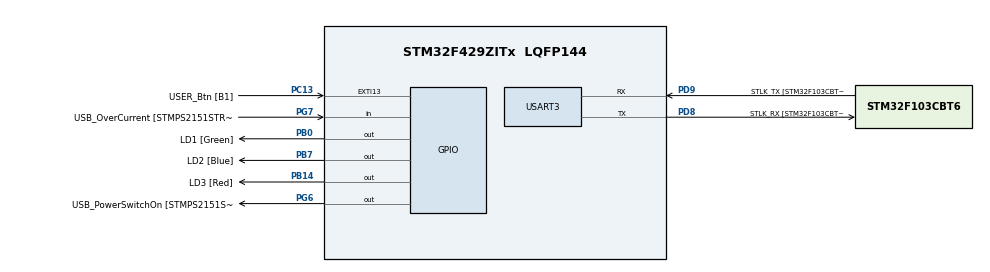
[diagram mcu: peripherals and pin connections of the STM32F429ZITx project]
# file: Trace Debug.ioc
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Mcu.Family=STM32F4
Mcu.Name=STM32F429ZITx
Mcu.Package=LQFP144
NVIC.PriorityGroup=NVIC_PRIORITYGROUP_4
PA13.GPIO_Label=TMS
PA13.Mode=Trace_Asynchronous_SW
PA13.Signal=SYS_JTMS-SWDIO
PA14.GPIO_Label=TCK
PA14.Mode=Trace_Asynchronous_SW
PA14.Signal=SYS_JTCK-SWCLK
PB0.GPIO_Label=LD1 [Green]
PB0.Signal=GPIO_Output
PB13.GPIO_Label=RMII_TXD1 [LAN8742A-CZ-TR_TXD1]
PB13.Signal=ETH_TXD1
PB14.GPIO_Label=LD3 [Red]
PB14.Signal=GPIO_Output
PB3.Mode=Trace_Asynchronous_SW
PB3.Signal=SYS_JTDO-SWO
PB7.GPIO_Label=LD2 [Blue]
PB7.Signal=GPIO_Output
PC13.GPIO_Label=USER_Btn [B1]
PC13.Signal=GPXTI13
PC14/OSC32_IN.Mode=LSE-External-Oscillator
PC14/OSC32_IN.Signal=RCC_OSC32_IN
PC15/OSC32_OUT.Mode=LSE-External-Oscillator
PC15/OSC32_OUT.Signal=RCC_OSC32_OUT
PD8.GPIO_Label=STLK_RX [STM32F103CBT6_PA3]
PD8.Mode=Asynchronous
PD8.Signal=USART3_TX
PD9.GPIO_Label=STLK_TX [STM32F103CBT6_PA2]
PD9.Mode=Asynchronous
PD9.Signal=USART3_RX
PG6.GPIO_Label=USB_PowerSwitchOn [STMPS2151STR_EN]
PG6.Signal=GPIO_Output
PG7.GPIO_Label=USB_OverCurrent [STMPS2151STR_FAULT]
PG7.Signal=GPIO_Input
PH0/OSC_IN.GPIO_Label=MCO [STM32F103CBT6_PA8]
PH0/OSC_IN.Mode=HSE-External-Clock-Source
PH0/OSC_IN.Signal=RCC_OSC_IN
PH1/OSC_OUT.Mode=HSE-External-Clock-Source
PH1/OSC_OUT.Signal=RCC_OSC_OUT
ProjectManager.HeapSize=0x800
ProjectManager.StackSize=0x800
ProjectManager.TargetToolchain=MDK-ARM V5.32
RCC.48MHZClocksFreq_Value=19428571.42857143
RCC.AHBFreq_Value=68000000
RCC.APB1CLKDivider=RCC_HCLK_DIV2
RCC.APB1Freq_Value=34000000
RCC.APB1TimFreq_Value=68000000
RCC.APB2CLKDivider=RCC_HCLK_DIV2
RCC.APB2Freq_Value=34000000
RCC.APB2TimFreq_Value=68000000
RCC.CortexFreq_Value=68000000
RCC.HCLKFreq_Value=68000000
RCC.HSE_VALUE=8000000
RCC.HSI_VALUE=16000000
RCC.PLLM=4
RCC.PLLMUL=RCC_PLL_MUL9
RCC.PLLN=68
RCC.PLLQ=7
RCC.PLLSourceVirtual=RCC_PLLSOURCE_HSE
RCC.PRESCALERUSB=RCC_USBCLKSOURCE_PLL_DIV1_5
RCC.SYSCLKFreq_VALUE=68000000
RCC.SYSCLKSource=RCC_SYSCLKSOURCE_PLLCLK
RCC.SYSCLKSourceVirtual=RCC_SYSCLKSOURCE_PLLCLK
RCC.USBFreq_Value=48000000
RCC.VCOOutputFreq_Value=136000000
USART3.VirtualMode=VM_ASYNC
board=NUCLEO-F429ZI

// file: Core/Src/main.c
/* USER CODE BEGIN Header */
/**
  ******************************************************************************
  * @file           : main.c
  * @brief          : Main program body
  ******************************************************************************
  * @attention
  *
  * <h2><center>&copy; Copyright (c) 2022 STMicroelectronics.
  * All rights reserved.</center></h2>
  *
  * This software component is licensed by ST under BSD 3-Clause license,
  * the "License"; You may not use this file except in compliance with the
  * License. You may obtain a copy of the License at:
  *                        opensource.org/licenses/BSD-3-Clause
  *
  ******************************************************************************
  */
/* USER CODE END Header */
#include "main.h"
#include "cramel.h"
#include "dwt_counter.h"
#include "math_helper.h"
#include "core_cm4_simd.h"

UART_HandleTypeDef huart3;

int16_t s16_curfitLine[RX_LEN];
float f32_curfitLine[RX_LEN];

/* USER CODE BEGIN PV */
struct __FILE
{
  int handle;
  /* Whatever you require here. If the only file you are using is */
  /* standard output using printf() for debugging, no file handling */
  /* is required. */
};
/* FILE is typedefТd in stdio.h. */
FILE __stdout;
int ferror(FILE *f)
{
  /* Your implementation of ferror(). */
  return 0;
}

int fputc(int ch, FILE *f)
{
  /* Place your implementation of fputc here */
  /* e.g. write a character to the USART1 and Loop until the end of transmission */
  HAL_UART_Transmit(&huart3, (uint8_t *)&ch, 1, 0xFFFF);

  return ch;
}
/* USER CODE END PV */

void SystemClock_Config(void);
static void MX_GPIO_Init(void);
static void MX_USART3_UART_Init(void);

int main(void)
{
  /* USER CODE BEGIN 1 */
	curfitCoef_t curfitCoef;
  uint64_t u64_bitmap;

  int16_t *s16_src;
  uint8_t *u8_curfitComp;
  float *f32_curfitLineRef;
  float f32_snr;
  float f32_accuracy;
  volatile float f32_duration = 0;
  volatile float f32_accuracyFrame = 0;
  /* USER CODE END 1 */

  /* MCU Configuration--------------------------------------------------------*/

  /* Reset of all peripherals, Initializes the Flash interface and the Systick. */
  HAL_Init();

  /* Configure the system clock */
  SystemClock_Config();

  /* Initialize all configured peripherals */
  MX_GPIO_Init();
  MX_USART3_UART_Init();
  /* USER CODE BEGIN 2 */
	SystemCoreClockUpdate();
  printf("\r\nINIT ARMCC OK @ %d MHz\r\n",(uint32_t)SystemCoreClock/1000000);

	uint32_t val1, val2;
	val1 = 1500;
	val2 = 3500;
	printf("\r\nSADD16 %d \r\n",__SADD16(val1, val2));

	for (uint8_t u8_i = 0; u8_i < TX_LEN; u8_i++)
  {
	  /* Set data */
	  s16_src = (int16_t*) &s16_reconstructed[u8_i];
	  u8_curfitComp = (uint8_t*) &u8_curvefitCompare[u8_i];
	  f32_curfitLineRef = (float*) &f32_curvefitLineRef[u8_i];
	  u64_bitmap = u64Func_GetBitmap(u8_curfitComp, RX_LEN);

	  /* Start timer */
	  DWT_Start();

	  /* Estimate */
	  vFunc_CurfitEstimation(s16_src, &curfitCoef, RX_LEN, u64_bitmap);
	  vFunc_GetCurveFitLine(s16_curfitLine, &curfitCoef, RX_LEN);

	  /* Stop timer */
	  f32_duration += DWT_GetTime_us();
	  DWT_Stop();

	  /* Calculate accuracy */
	  vFunc_ConvertS16toFloat(s16_curfitLine, f32_curfitLine, RX_LEN);
	  f32_snr = arm_snr_f32(f32_curfitLineRef, f32_curfitLine, RX_LEN);
	  f32_accuracy = 100.0f - (100.0f / f32_snr);
	  f32_accuracyFrame += f32_accuracy;

	  /* Print to stdout */
	  printf("Accuracy TX[%d]: %.2f %%\r\n", u8_i, f32_accuracy);
  }

	f32_accuracyFrame /= TX_LEN;
  f32_duration /= 1000;

  printf("\r\n");
  printf("Frame Accuracy: %.2f %%\r\n", f32_accuracyFrame);
  printf("Frame Duration: %.2f ms\r\n", f32_duration);
  /* USER CODE END 2 */

  /* Infinite loop */
  while (1)
  {

  }
}

void SystemClock_Config(void)
{
  RCC_OscInitTypeDef RCC_OscInitStruct = {0};
  RCC_ClkInitTypeDef RCC_ClkInitStruct = {0};

  /** Configure the main internal regulator output voltage
  */
  __HAL_RCC_PWR_CLK_ENABLE();
  __HAL_PWR_VOLTAGESCALING_CONFIG(PWR_REGULATOR_VOLTAGE_SCALE1);
  /** Initializes the RCC Oscillators according to the specified parameters
  * in the RCC_OscInitTypeDef structure.
  */
  RCC_OscInitStruct.OscillatorType = RCC_OSCILLATORTYPE_HSE;
  RCC_OscInitStruct.HSEState = RCC_HSE_BYPASS;
  RCC_OscInitStruct.PLL.PLLState = RCC_PLL_ON;
  RCC_OscInitStruct.PLL.PLLSource = RCC_PLLSOURCE_HSE;
  RCC_OscInitStruct.PLL.PLLM = 4;
  RCC_OscInitStruct.PLL.PLLN = 68;
  RCC_OscInitStruct.PLL.PLLP = RCC_PLLP_DIV2;
  RCC_OscInitStruct.PLL.PLLQ = 7;
  if (HAL_RCC_OscConfig(&RCC_OscInitStruct) != HAL_OK)
  {
    Error_Handler();
  }
  /** Initializes the CPU, AHB and APB buses clocks
  */
  RCC_ClkInitStruct.ClockType = RCC_CLOCKTYPE_HCLK|RCC_CLOCKTYPE_SYSCLK
                              |RCC_CLOCKTYPE_PCLK1|RCC_CLOCKTYPE_PCLK2;
  RCC_ClkInitStruct.SYSCLKSource = RCC_SYSCLKSOURCE_PLLCLK;
  RCC_ClkInitStruct.AHBCLKDivider = RCC_SYSCLK_DIV1;
  RCC_ClkInitStruct.APB1CLKDivider = RCC_HCLK_DIV4;
  RCC_ClkInitStruct.APB2CLKDivider = RCC_HCLK_DIV2;

  if (HAL_RCC_ClockConfig(&RCC_ClkInitStruct, FLASH_LATENCY_2) != HAL_OK)
  {
    Error_Handler();
  }
}

static void MX_USART3_UART_Init(void)
{

  huart3.Instance = USART3;
  huart3.Init.BaudRate = 115200;
  huart3.Init.WordLength = UART_WORDLENGTH_8B;
  huart3.Init.StopBits = UART_STOPBITS_1;
  huart3.Init.Parity = UART_PARITY_NONE;
  huart3.Init.Mode = UART_MODE_TX_RX;
  huart3.Init.HwFlowCtl = UART_HWCONTROL_NONE;
  huart3.Init.OverSampling = UART_OVERSAMPLING_16;
  if (HAL_UART_Init(&huart3) != HAL_OK)
  {
    Error_Handler();
  }

}

static void MX_GPIO_Init(void)
{
  GPIO_InitTypeDef GPIO_InitStruct = {0};

  /* GPIO Ports Clock Enable */
  __HAL_RCC_GPIOC_CLK_ENABLE();
  __HAL_RCC_GPIOH_CLK_ENABLE();
  __HAL_RCC_GPIOB_CLK_ENABLE();
  __HAL_RCC_GPIOD_CLK_ENABLE();
  __HAL_RCC_GPIOG_CLK_ENABLE();
  __HAL_RCC_GPIOA_CLK_ENABLE();

  /*Configure GPIO pin Output Level */
  HAL_GPIO_WritePin(GPIOB, LD1_Pin|LD3_Pin|LD2_Pin, GPIO_PIN_RESET);

  /*Configure GPIO pin Output Level */
  HAL_GPIO_WritePin(USB_PowerSwitchOn_GPIO_Port, USB_PowerSwitchOn_Pin, GPIO_PIN_RESET);

  /*Configure GPIO pin : USER_Btn_Pin */
  GPIO_InitStruct.Pin = USER_Btn_Pin;
  GPIO_InitStruct.Mode = GPIO_MODE_IT_RISING;
  GPIO_InitStruct.Pull = GPIO_NOPULL;
  HAL_GPIO_Init(USER_Btn_GPIO_Port, &GPIO_InitStruct);

  /*Configure GPIO pins : LD1_Pin LD3_Pin LD2_Pin */
  GPIO_InitStruct.Pin = LD1_Pin|LD3_Pin|LD2_Pin;
  GPIO_InitStruct.Mode = GPIO_MODE_OUTPUT_PP;
  GPIO_InitStruct.Pull = GPIO_NOPULL;
  GPIO_InitStruct.Speed = GPIO_SPEED_FREQ_LOW;
  HAL_GPIO_Init(GPIOB, &GPIO_InitStruct);

  /*Configure GPIO pin : RMII_TXD1_Pin */
  GPIO_InitStruct.Pin = RMII_TXD1_Pin;
  GPIO_InitStruct.Mode = GPIO_MODE_AF_PP;
  GPIO_InitStruct.Pull = GPIO_NOPULL;
  GPIO_InitStruct.Speed = GPIO_SPEED_FREQ_VERY_HIGH;
  GPIO_InitStruct.Alternate = GPIO_AF11_ETH;
  HAL_GPIO_Init(RMII_TXD1_GPIO_Port, &GPIO_InitStruct);

  /*Configure GPIO pin : USB_PowerSwitchOn_Pin */
  GPIO_InitStruct.Pin = USB_PowerSwitchOn_Pin;
  GPIO_InitStruct.Mode = GPIO_MODE_OUTPUT_PP;
  GPIO_InitStruct.Pull = GPIO_NOPULL;
  GPIO_InitStruct.Speed = GPIO_SPEED_FREQ_LOW;
  HAL_GPIO_Init(USB_PowerSwitchOn_GPIO_Port, &GPIO_InitStruct);

  /*Configure GPIO pin : USB_OverCurrent_Pin */
  GPIO_InitStruct.Pin = USB_OverCurrent_Pin;
  GPIO_InitStruct.Mode = GPIO_MODE_INPUT;
  GPIO_InitStruct.Pull = GPIO_NOPULL;
  HAL_GPIO_Init(USB_OverCurrent_GPIO_Port, &GPIO_InitStruct);

}

void Error_Handler(void)
{
  __disable_irq();
  while (1)
  {
  }
}

/************************ (C) COPYRIGHT STMicroelectronics *****END OF FILE****/
